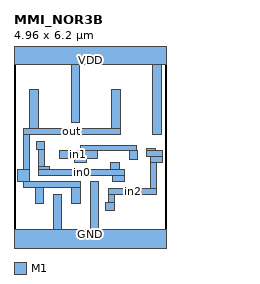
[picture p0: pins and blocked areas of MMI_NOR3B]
MACRO MMI_NOR3B
	CLASS CORE ;
	FOREIGN MMI_NOR3B 0 0 ;
	SIZE 4.96 BY 6.2 ;
	SYMMETRY X Y ;
	SITE CORE1 ;
	PIN out
		DIRECTION output ;
		USE SIGNAL ;
		PORT
			LAYER M1 ;
			RECT 0.52 3.695 0.8 4.975 ;
			LAYER M1 ;
			RECT 3.195 3.695 3.475 4.975 ;
			LAYER M1 ;
			RECT 0.305 3.505 3.475 3.695 ;
			LAYER M1 ;
			RECT 0.305 2.36 0.5 3.505 ;
			LAYER M1 ;
			RECT 0.12 1.98 0.5 2.36 ;
			LAYER M1 ;
			RECT 0.305 1.97 0.5 1.98 ;
			LAYER M1 ;
			RECT 0.305 1.965 2.135 1.97 ;
			LAYER M1 ;
			RECT 0.305 1.775 2.17 1.965 ;
			LAYER M1 ;
			RECT 0.695 1.265 0.975 1.775 ;
			LAYER M1 ;
			RECT 1.89 1.265 2.17 1.775 ;
		END
		AntennaDiffArea 1.92885 ;
	END out
	PIN in1
		DIRECTION input ;
		USE SIGNAL ;
		PORT
			LAYER M1 ;
			RECT 2.17 2.995 3.995 3.165 ;
			LAYER M1 ;
			RECT 1.49 2.98 3.995 2.995 ;
			LAYER M1 ;
			RECT 1.49 2.97 4.04 2.98 ;
			LAYER M1 ;
			RECT 1.49 2.715 2.71 2.97 ;
			LAYER M1 ;
			RECT 1.98 2.6 2.36 2.715 ;
			LAYER M1 ;
			RECT 3.76 2.7 4.04 2.97 ;
		END
		AntennaGateArea 0.8085 ;
	END in1
	PIN GND
		DIRECTION inout ;
		USE GROUND ;
		PORT
			LAYER M1 ;
			RECT 1.285 0.42 1.565 1.545 ;
			LAYER M1 ;
			RECT 2.48 0.42 2.76 1.965 ;
			LAYER M1 ;
			RECT 0 -0.42 4.96 0.42 ;
		END
	END GND
	PIN in2
		DIRECTION input ;
		USE SIGNAL ;
		PORT
			LAYER M1 ;
			RECT 4.33 2.98 4.61 3.06 ;
			LAYER M1 ;
			RECT 4.33 2.78 4.84 2.98 ;
			LAYER M1 ;
			RECT 4.46 2.6 4.84 2.78 ;
			LAYER M1 ;
			RECT 4.46 1.745 4.655 2.6 ;
			LAYER M1 ;
			RECT 3.085 1.555 4.655 1.745 ;
			LAYER M1 ;
			RECT 3.085 1.295 3.275 1.555 ;
			LAYER M1 ;
			RECT 2.995 1.015 3.275 1.295 ;
		END
		AntennaGateArea 0.8085 ;
	END in2
	PIN VDD
		DIRECTION inout ;
		USE POWER ;
		PORT
			LAYER M1 ;
			RECT 0 5.78 4.96 6.62 ;
			LAYER M1 ;
			RECT 1.865 3.915 2.145 5.78 ;
			LAYER M1 ;
			RECT 4.525 3.505 4.805 5.78 ;
		END
	END VDD
	PIN in0
		DIRECTION input ;
		USE SIGNAL ;
		PORT
			LAYER M1 ;
			RECT 0.72 3.005 1 3.285 ;
			LAYER M1 ;
			RECT 0.81 2.45 1 3.005 ;
			LAYER M1 ;
			RECT 0.81 2.365 1.17 2.45 ;
			LAYER M1 ;
			RECT 3.155 2.365 3.435 2.58 ;
			LAYER M1 ;
			RECT 0.81 2.36 3.435 2.365 ;
			LAYER M1 ;
			RECT 0.81 2.175 3.6 2.36 ;
			LAYER M1 ;
			RECT 0.89 2.17 1.17 2.175 ;
			LAYER M1 ;
			RECT 3.22 1.98 3.6 2.175 ;
		END
		AntennaGateArea 0.8085 ;
	END in0
	OBS
	END
END MMI_NOR3B
